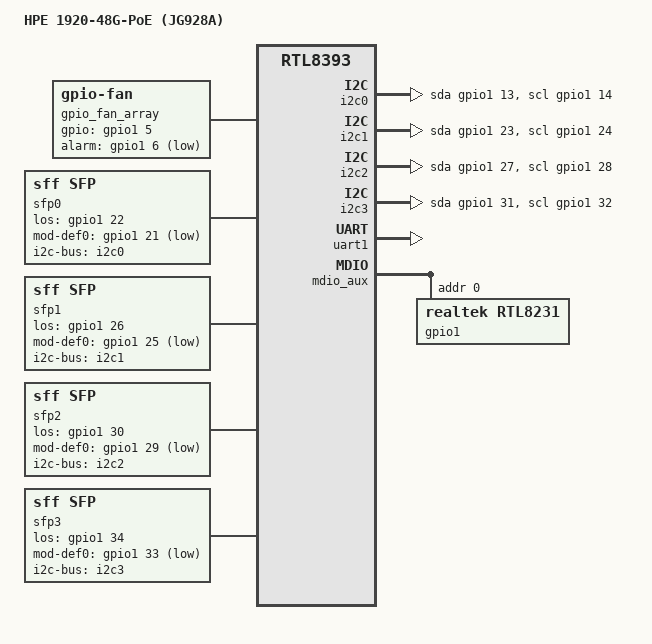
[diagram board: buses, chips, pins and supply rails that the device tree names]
// SPDX-License-Identifier: GPL-2.0-or-later OR MIT

#include "rtl8393_hpe_1920.dtsi"

/ {
	compatible = "hpe,1920-48g-poe", "realtek,rtl8393-soc";
	model = "HPE 1920-48G-PoE (JG928A)";

	gpio_fan_array {
		compatible = "gpio-fan";

		gpios = <&gpio1 5 GPIO_ACTIVE_HIGH>;
		gpio-fan,speed-map =    <5000 0>,
					<8200 1>;

		alarm-gpios = <&gpio1 6 GPIO_ACTIVE_LOW>;
		#cooling-cells = <2>;
	};

	i2c0: i2c-gpio-0 {
		compatible = "i2c-gpio";
		sda-gpios = <&gpio1 13 (GPIO_ACTIVE_HIGH | GPIO_OPEN_DRAIN)>;
		scl-gpios = <&gpio1 14 (GPIO_ACTIVE_HIGH | GPIO_OPEN_DRAIN)>;
		i2c-gpio,delay-us = <2>;
		#address-cells = <1>;
		#size-cells = <0>;
	};

	sfp0: sfp-p49 {
		compatible = "sff,sfp";
		i2c-bus = <&i2c0>;
		los-gpio = <&gpio1 22 GPIO_ACTIVE_HIGH>;
		mod-def0-gpio = <&gpio1 21 GPIO_ACTIVE_LOW>;
		// tx-fault unconnected (TODO?)
		// tx-disable connected to RTL8214FC (TODO?)
	};

	i2c1: i2c-gpio-1 {
		compatible = "i2c-gpio";
		sda-gpios = <&gpio1 23 (GPIO_ACTIVE_HIGH | GPIO_OPEN_DRAIN)>;
		scl-gpios = <&gpio1 24 (GPIO_ACTIVE_HIGH | GPIO_OPEN_DRAIN)>;
		i2c-gpio,delay-us = <2>;
		#address-cells = <1>;
		#size-cells = <0>;
	};

	sfp1: sfp-p50 {
		compatible = "sff,sfp";
		i2c-bus = <&i2c1>;
		los-gpio = <&gpio1 26 GPIO_ACTIVE_HIGH>;
		mod-def0-gpio = <&gpio1 25 GPIO_ACTIVE_LOW>;
		// tx-fault unconnected (TODO?)
		// tx-disable connected to RTL8214FC (TODO?)
	};

	i2c2: i2c-gpio-2 {
		compatible = "i2c-gpio";
		sda-gpios = <&gpio1 27 (GPIO_ACTIVE_HIGH | GPIO_OPEN_DRAIN)>;
		scl-gpios = <&gpio1 28 (GPIO_ACTIVE_HIGH | GPIO_OPEN_DRAIN)>;
		i2c-gpio,delay-us = <2>;
		#address-cells = <1>;
		#size-cells = <0>;
	};

	sfp2: sfp-p51 {
		compatible = "sff,sfp";
		i2c-bus = <&i2c2>;
		los-gpio = <&gpio1 30 GPIO_ACTIVE_HIGH>;
		mod-def0-gpio = <&gpio1 29 GPIO_ACTIVE_LOW>;
		// tx-fault unconnected (TODO?)
		// tx-disable connected to RTL8214FC (TODO?)
	};

	i2c3: i2c-gpio-3 {
		compatible = "i2c-gpio";
		sda-gpios = <&gpio1 31 (GPIO_ACTIVE_HIGH | GPIO_OPEN_DRAIN)>;
		scl-gpios = <&gpio1 32 (GPIO_ACTIVE_HIGH | GPIO_OPEN_DRAIN)>;
		i2c-gpio,delay-us = <2>;
		#address-cells = <1>;
		#size-cells = <0>;
	};

	sfp3: sfp-p52 {
		compatible = "sff,sfp";
		i2c-bus = <&i2c3>;
		los-gpio = <&gpio1 34 GPIO_ACTIVE_HIGH>;
		mod-def0-gpio = <&gpio1 33 GPIO_ACTIVE_LOW>;
		// tx-fault unconnected (TODO?)
		// tx-disable connected to RTL8214FC (TODO?)
	};
};

&mdio_bus1 {
	PHY_C22_SFP(48, 24, 0)
	PHY_C22_SFP(49, 25, 1)
	PHY_C22_SFP(50, 26, 2)
	PHY_C22_SFP(51, 27, 3)
};

&switch0 {
	ethernet-ports {
		SWITCH_PORT_SDS(48, 49, 12, 0, qsgmii)
		SWITCH_PORT_SDS(49, 50, 12, 1, qsgmii)
		SWITCH_PORT_SDS(50, 51, 12, 2, qsgmii)
		SWITCH_PORT_SDS(51, 52, 12, 3, qsgmii)
	};
};

&port48 {
	nvmem-cells = <&macaddr_factory 50>;
	nvmem-cell-names = "mac-address";
};

&port49 {
	nvmem-cells = <&macaddr_factory 51>;
	nvmem-cell-names = "mac-address";
};

&port50 {
	nvmem-cells = <&macaddr_factory 52>;
	nvmem-cell-names = "mac-address";
};

&port51 {
	nvmem-cells = <&macaddr_factory 53>;
	nvmem-cell-names = "mac-address";
};

&uart1 {
	status = "okay";
};

&mdio_aux {
	status = "okay";

	gpio1: expander@0 {
		compatible = "realtek,rtl8231";
		reg = <0>;

		gpio-controller;
		#gpio-cells = <2>;
		gpio-ranges = <&gpio1 0 0 37>;

		led-controller {
			compatible = "realtek,rtl8231-leds";
			status = "disabled";
		};
	};
};
